VERSION 5.7 ;
  NOWIREEXTENSIONATPIN ON ;
  DIVIDERCHAR "/" ;
  BUSBITCHARS "[]" ;
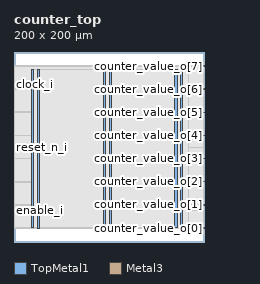
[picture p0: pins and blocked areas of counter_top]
MACRO counter_top
  CLASS BLOCK ;
  FOREIGN counter_top ;
  ORIGIN 0.000 0.000 ;
  SIZE 200.000 BY 200.000 ;
  PIN VDD
    DIRECTION INOUT ;
    USE POWER ;
    PORT
      LAYER TopMetal1 ;
        RECT 18.260 14.900 20.460 181.660 ;
    END
    PORT
      LAYER TopMetal1 ;
        RECT 93.860 14.900 96.060 181.660 ;
    END
    PORT
      LAYER TopMetal1 ;
        RECT 169.460 14.900 171.660 181.660 ;
    END
  END VDD
  PIN VSS
    DIRECTION INOUT ;
    USE GROUND ;
    PORT
      LAYER TopMetal1 ;
        RECT 24.460 14.490 26.660 182.070 ;
    END
    PORT
      LAYER TopMetal1 ;
        RECT 100.060 14.490 102.260 182.070 ;
    END
    PORT
      LAYER TopMetal1 ;
        RECT 175.660 14.490 177.860 182.070 ;
    END
  END VSS
  PIN clock_i
    DIRECTION INPUT ;
    USE SIGNAL ;
    ANTENNAGATEAREA 1.450800 ;
    PORT
      LAYER Metal3 ;
        RECT 0.000 165.700 0.400 166.100 ;
    END
  END clock_i
  PIN counter_value_o[0]
    DIRECTION OUTPUT ;
    USE SIGNAL ;
    ANTENNADIFFAREA 0.708600 ;
    PORT
      LAYER Metal3 ;
        RECT 199.600 14.500 200.000 14.900 ;
    END
  END counter_value_o[0]
  PIN counter_value_o[1]
    DIRECTION OUTPUT ;
    USE SIGNAL ;
    ANTENNADIFFAREA 0.708600 ;
    PORT
      LAYER Metal3 ;
        RECT 199.600 38.860 200.000 39.260 ;
    END
  END counter_value_o[1]
  PIN counter_value_o[2]
    DIRECTION OUTPUT ;
    USE SIGNAL ;
    ANTENNADIFFAREA 0.708600 ;
    PORT
      LAYER Metal3 ;
        RECT 199.600 63.220 200.000 63.620 ;
    END
  END counter_value_o[2]
  PIN counter_value_o[3]
    DIRECTION OUTPUT ;
    USE SIGNAL ;
    ANTENNADIFFAREA 0.708600 ;
    PORT
      LAYER Metal3 ;
        RECT 199.600 87.580 200.000 87.980 ;
    END
  END counter_value_o[3]
  PIN counter_value_o[4]
    DIRECTION OUTPUT ;
    USE SIGNAL ;
    ANTENNADIFFAREA 0.708600 ;
    PORT
      LAYER Metal3 ;
        RECT 199.600 111.940 200.000 112.340 ;
    END
  END counter_value_o[4]
  PIN counter_value_o[5]
    DIRECTION OUTPUT ;
    USE SIGNAL ;
    ANTENNADIFFAREA 0.708600 ;
    PORT
      LAYER Metal3 ;
        RECT 199.600 136.300 200.000 136.700 ;
    END
  END counter_value_o[5]
  PIN counter_value_o[6]
    DIRECTION OUTPUT ;
    USE SIGNAL ;
    ANTENNADIFFAREA 0.708600 ;
    PORT
      LAYER Metal3 ;
        RECT 199.600 160.660 200.000 161.060 ;
    END
  END counter_value_o[6]
  PIN counter_value_o[7]
    DIRECTION OUTPUT ;
    USE SIGNAL ;
    ANTENNADIFFAREA 0.708600 ;
    PORT
      LAYER Metal3 ;
        RECT 199.600 185.020 200.000 185.420 ;
    END
  END counter_value_o[7]
  PIN enable_i
    DIRECTION INPUT ;
    USE SIGNAL ;
    ANTENNAGATEAREA 0.180700 ;
    PORT
      LAYER Metal3 ;
        RECT 0.000 32.980 0.400 33.380 ;
    END
  END enable_i
  PIN reset_n_i
    DIRECTION INPUT ;
    USE SIGNAL ;
    ANTENNAGATEAREA 0.180700 ;
    PORT
      LAYER Metal3 ;
        RECT 0.000 99.340 0.400 99.740 ;
    END
  END reset_n_i
  OBS
      LAYER GatPoly ;
        RECT 5.760 14.970 193.920 181.590 ;
      LAYER Metal1 ;
        RECT 5.760 14.900 193.920 181.660 ;
      LAYER Metal2 ;
        RECT 6.135 14.555 194.500 185.365 ;
      LAYER Metal3 ;
        RECT 0.400 184.810 199.390 185.320 ;
        RECT 0.400 166.310 199.600 184.810 ;
        RECT 0.610 165.490 199.600 166.310 ;
        RECT 0.400 161.270 199.600 165.490 ;
        RECT 0.400 160.450 199.390 161.270 ;
        RECT 0.400 136.910 199.600 160.450 ;
        RECT 0.400 136.090 199.390 136.910 ;
        RECT 0.400 112.550 199.600 136.090 ;
        RECT 0.400 111.730 199.390 112.550 ;
        RECT 0.400 99.950 199.600 111.730 ;
        RECT 0.610 99.130 199.600 99.950 ;
        RECT 0.400 88.190 199.600 99.130 ;
        RECT 0.400 87.370 199.390 88.190 ;
        RECT 0.400 63.830 199.600 87.370 ;
        RECT 0.400 63.010 199.390 63.830 ;
        RECT 0.400 39.470 199.600 63.010 ;
        RECT 0.400 38.650 199.390 39.470 ;
        RECT 0.400 33.590 199.600 38.650 ;
        RECT 0.610 32.770 199.600 33.590 ;
        RECT 0.400 15.110 199.600 32.770 ;
        RECT 0.400 14.600 199.390 15.110 ;
      LAYER Metal4 ;
        RECT 18.440 14.975 183.460 181.585 ;
      LAYER Metal5 ;
        RECT 18.395 14.810 177.725 181.750 ;
  END
END counter_top
END LIBRARY

